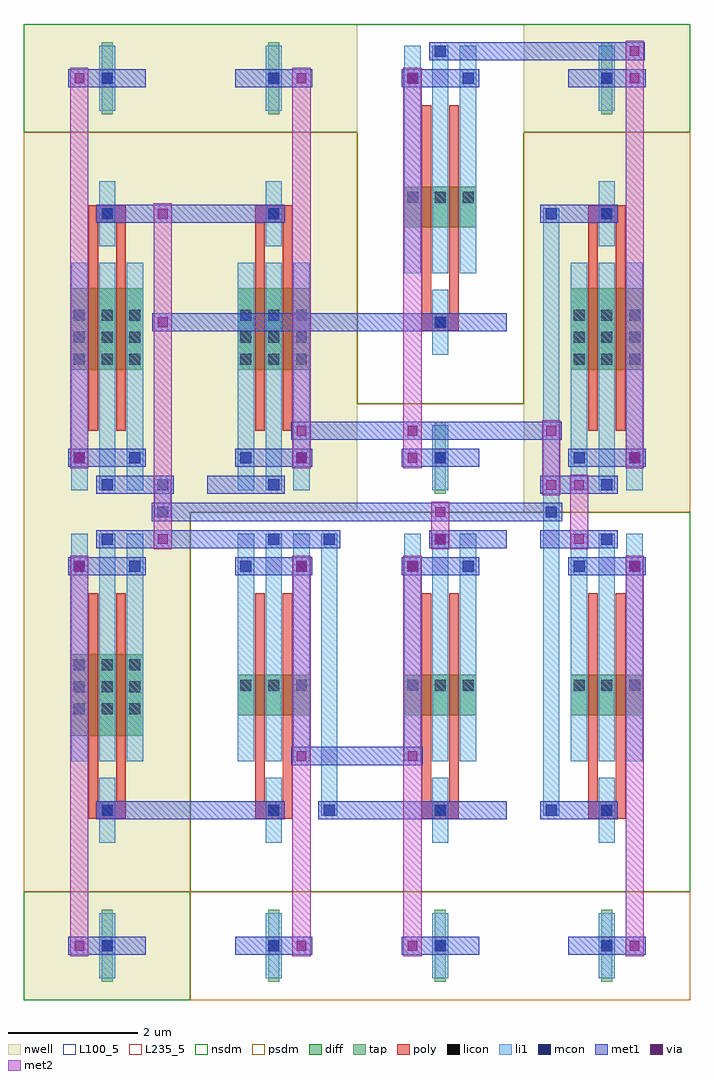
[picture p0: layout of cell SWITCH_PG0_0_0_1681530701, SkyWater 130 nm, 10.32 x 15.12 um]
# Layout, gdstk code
from math import pi, radians
import gdstk
lib = gdstk.Library(unit=1e-6, precision=1e-09)
def R(c, l, rs):  # rectangles x0, y0, x1, y1
    for r in rs: c.add(gdstk.rectangle(r[:2], r[2:], *l))
def A(c, l, x, y, w, h, nx, ny, dx, dy):  # array of equal rectangles
    R(c, l, [(x+i*dx, y+j*dy, x+i*dx+w, y+j*dy+h) for i in range(nx) for j in range(ny)])
def P(c, l, *ps):  # polygons
    for p in ps: c.add(gdstk.Polygon(p, *l))
nwell = (64, 20)
diff = (65, 20)
tap = (65, 44)
poly = (66, 20)
licon = (66, 44)
li1 = (67, 20)
mcon = (67, 44)
met1 = (68, 20)
via = (68, 44)
met2 = (69, 20)
nsdm = (93, 44)
psdm = (94, 20)
L100_5 = (100, 5)
L235_5 = (235, 5)

nmos_s_18927041_x1_y1_16 = lib.new_cell('NMOS_S_18927041_X1_Y1_1681530695_1681530696_1681530701')
R(nmos_s_18927041_x1_y1_16, diff, [(0.735,2.52,1.845,3.15)])
R(nmos_s_18927041_x1_y1_16, tap, [(1.205,6.16,1.375,7.28)])
R(nmos_s_18927041_x1_y1_16, poly, [(1,1.26,1.15,4.62), (1.43,1.26,1.58,4.62), (1,4.485,1.58,4.755)])
A(nmos_s_18927041_x1_y1_16, licon, 0.775, 2.6, 0.17, 0.17, 3, 1, 0.43, 0)
R(nmos_s_18927041_x1_y1_16, licon, [(1.205,4.535,1.375,4.705), (1.205,6.635,1.375,6.805)])
A(nmos_s_18927041_x1_y1_16, li1, 0.735, 0.335, 0.25, 3.53, 3, 1, 0.43, 0)
R(nmos_s_18927041_x1_y1_16, li1, [(1.165,4.115,1.415,5.125), (1.165,6.215,1.415,7.225)])
R(nmos_s_18927041_x1_y1_16, mcon, [(1.205,0.335,1.375,0.505), (0.775,0.755,0.945,0.925), (1.635,0.755,1.805,0.925), (1.205,4.535,1.375,4.705), (1.205,6.635,1.375,6.805)])
R(nmos_s_18927041_x1_y1_16, met1, [(0.26,0.28,1.46,0.56), (0.69,0.7,1.89,0.98), (0.26,4.48,1.46,4.76), (0.69,6.58,1.89,6.86)])
R(nmos_s_18927041_x1_y1_16, via, [(1.645,0.765,1.795,0.915), (1.645,6.645,1.795,6.795)])
R(nmos_s_18927041_x1_y1_16, met2, [(1.58,0.68,1.86,6.88)])
R(nmos_s_18927041_x1_y1_16, nsdm, [(0,0,2.58,5.88)])
R(nmos_s_18927041_x1_y1_16, psdm, [(0,5.88,2.58,7.56)])
R(nmos_s_18927041_x1_y1_16, L100_5, [(0,0,2.58,7.56)])

pmos_s_92403763_x1_y1_16 = lib.new_cell('PMOS_S_92403763_X1_Y1_1681530696_1681530696_1681530701')
R(pmos_s_92403763_x1_y1_16, nwell, [(0,0,2.58,7.56)])
R(pmos_s_92403763_x1_y1_16, diff, [(0.735,2.205,1.845,3.465)])
R(pmos_s_92403763_x1_y1_16, tap, [(1.205,6.16,1.375,7.28)])
R(pmos_s_92403763_x1_y1_16, poly, [(1,1.26,1.15,4.62), (1.43,1.26,1.58,4.62), (1,4.485,1.58,4.755)])
A(pmos_s_92403763_x1_y1_16, licon, 0.775, 2.285, 0.17, 0.17, 3, 3, 0.43, 0.34)
R(pmos_s_92403763_x1_y1_16, licon, [(1.205,4.535,1.375,4.705), (1.205,6.635,1.375,6.805)])
A(pmos_s_92403763_x1_y1_16, li1, 0.735, 0.335, 0.25, 3.53, 3, 1, 0.43, 0)
R(pmos_s_92403763_x1_y1_16, li1, [(1.165,4.115,1.415,5.125), (1.165,6.215,1.415,7.225)])
R(pmos_s_92403763_x1_y1_16, mcon, [(1.205,0.335,1.375,0.505), (0.775,0.755,0.945,0.925), (1.635,0.755,1.805,0.925), (1.205,4.535,1.375,4.705), (1.205,6.635,1.375,6.805)])
R(pmos_s_92403763_x1_y1_16, met1, [(0.26,0.28,1.46,0.56), (0.69,0.7,1.89,0.98), (0.26,4.48,1.46,4.76), (0.69,6.58,1.89,6.86)])
R(pmos_s_92403763_x1_y1_16, via, [(1.645,0.765,1.795,0.915), (1.645,6.645,1.795,6.795)])
R(pmos_s_92403763_x1_y1_16, met2, [(1.58,0.68,1.86,6.88)])
R(pmos_s_92403763_x1_y1_16, nsdm, [(0,5.88,2.58,7.56)])
R(pmos_s_92403763_x1_y1_16, psdm, [(0,0,2.58,5.88)])
R(pmos_s_92403763_x1_y1_16, L100_5, [(0,0,2.58,7.56)])

inv_26057185_pg0_0_0_168 = lib.new_cell('INV_26057185_PG0_0_0_1681530696_1681530701')
R(inv_26057185_pg0_0_0_168, li1, [(0.305,2.855,0.555,3.025), (0.305,2.855,0.555,3.025), (0.305,2.94,0.555,12.18), (0.305,12.095,0.555,12.265), (0.305,12.095,0.555,12.265)])
R(inv_26057185_pg0_0_0_168, mcon, [(0.345,2.855,0.515,3.025), (0.345,2.855,0.515,3.025), (0.345,12.095,0.515,12.265), (0.345,12.095,0.515,12.265)])
R(inv_26057185_pg0_0_0_168, met1, [(0.26,2.8,0.6,3.08), (0.26,2.8,0.6,3.08), (0.7,7,1.02,7.28), (0.7,7,1.02,7.28), (0.7,7.84,1.02,8.12), (0.7,7.84,1.02,8.12), (0.26,12.04,0.6,12.32), (0.26,12.04,0.6,12.32)])
P(inv_26057185_pg0_0_0_168, met1, [(0,0),(0,0),(0,0),(0,0)],
  [(0,0),(0,0),(0,0),(0,0)],
  [(0,0),(0,0),(0,0),(0,0)],
  [(0,0),(0,0),(0,0),(0,0)])
R(inv_26057185_pg0_0_0_168, via, [(0.785,7.065,0.935,7.215), (0.785,7.065,0.935,7.215), (0.785,7.905,0.935,8.055), (0.785,7.905,0.935,8.055)])
R(inv_26057185_pg0_0_0_168, met2, [(0.72,6.98,1,7.3), (0.72,6.98,1,7.3), (0.72,7.14,1,7.98), (0.72,7.82,1,8.14), (0.72,7.82,1,8.14)])
P(inv_26057185_pg0_0_0_168, met2, [(0,0),(0,0),(0,0),(0,0)],
  [(0,0),(0,0),(0,0),(0,0)])
R(inv_26057185_pg0_0_0_168, L235_5, [(0,0,2.58,15.12)])
inv_26057185_pg0_0_0_168.add(gdstk.Reference(nmos_s_18927041_x1_y1_16, (0,7.56), x_reflection=True))
inv_26057185_pg0_0_0_168.add(gdstk.Reference(pmos_s_92403763_x1_y1_16, (0,7.56)))

c_nmos_s_18927041_x1_y1_16 = lib.new_cell('NMOS_S_18927041_X1_Y1_1681530697_1681530701')
R(c_nmos_s_18927041_x1_y1_16, diff, [(0.735,2.52,1.845,3.15)])
R(c_nmos_s_18927041_x1_y1_16, tap, [(1.205,6.16,1.375,7.28)])
R(c_nmos_s_18927041_x1_y1_16, poly, [(1,1.26,1.15,4.62), (1.43,1.26,1.58,4.62), (1,4.485,1.58,4.755)])
A(c_nmos_s_18927041_x1_y1_16, licon, 0.775, 2.6, 0.17, 0.17, 3, 1, 0.43, 0)
R(c_nmos_s_18927041_x1_y1_16, licon, [(1.205,4.535,1.375,4.705), (1.205,6.635,1.375,6.805)])
A(c_nmos_s_18927041_x1_y1_16, li1, 0.735, 0.335, 0.25, 3.53, 3, 1, 0.43, 0)
R(c_nmos_s_18927041_x1_y1_16, li1, [(1.165,4.115,1.415,5.125), (1.165,6.215,1.415,7.225)])
R(c_nmos_s_18927041_x1_y1_16, mcon, [(1.205,0.335,1.375,0.505), (0.775,0.755,0.945,0.925), (1.635,0.755,1.805,0.925), (1.205,4.535,1.375,4.705), (1.205,6.635,1.375,6.805)])
R(c_nmos_s_18927041_x1_y1_16, met1, [(0.26,0.28,1.46,0.56), (0.69,0.7,1.89,0.98), (0.26,4.48,1.46,4.76), (0.69,6.58,1.89,6.86)])
R(c_nmos_s_18927041_x1_y1_16, via, [(1.645,0.765,1.795,0.915), (1.645,6.645,1.795,6.795)])
R(c_nmos_s_18927041_x1_y1_16, met2, [(1.58,0.68,1.86,6.88)])
R(c_nmos_s_18927041_x1_y1_16, nsdm, [(0,0,2.58,5.88)])
R(c_nmos_s_18927041_x1_y1_16, psdm, [(0,5.88,2.58,7.56)])
R(c_nmos_s_18927041_x1_y1_16, L100_5, [(0,0,2.58,7.56)])

c_pmos_s_92403763_x1_y1_16 = lib.new_cell('PMOS_S_92403763_X1_Y1_1681530698_1681530701')
R(c_pmos_s_92403763_x1_y1_16, nwell, [(0,0,2.58,7.56)])
R(c_pmos_s_92403763_x1_y1_16, diff, [(0.735,2.205,1.845,3.465)])
R(c_pmos_s_92403763_x1_y1_16, tap, [(1.205,6.16,1.375,7.28)])
R(c_pmos_s_92403763_x1_y1_16, poly, [(1,1.26,1.15,4.62), (1.43,1.26,1.58,4.62), (1,4.485,1.58,4.755)])
A(c_pmos_s_92403763_x1_y1_16, licon, 0.775, 2.285, 0.17, 0.17, 3, 3, 0.43, 0.34)
R(c_pmos_s_92403763_x1_y1_16, licon, [(1.205,4.535,1.375,4.705), (1.205,6.635,1.375,6.805)])
A(c_pmos_s_92403763_x1_y1_16, li1, 0.735, 0.335, 0.25, 3.53, 3, 1, 0.43, 0)
R(c_pmos_s_92403763_x1_y1_16, li1, [(1.165,4.115,1.415,5.125), (1.165,6.215,1.415,7.225)])
R(c_pmos_s_92403763_x1_y1_16, mcon, [(1.205,0.335,1.375,0.505), (0.775,0.755,0.945,0.925), (1.635,0.755,1.805,0.925), (1.205,4.535,1.375,4.705), (1.205,6.635,1.375,6.805)])
R(c_pmos_s_92403763_x1_y1_16, met1, [(0.26,0.28,1.46,0.56), (0.69,0.7,1.89,0.98), (0.26,4.48,1.46,4.76), (0.69,6.58,1.89,6.86)])
R(c_pmos_s_92403763_x1_y1_16, via, [(1.645,0.765,1.795,0.915), (1.645,6.645,1.795,6.795)])
R(c_pmos_s_92403763_x1_y1_16, met2, [(1.58,0.68,1.86,6.88)])
R(c_pmos_s_92403763_x1_y1_16, nsdm, [(0,5.88,2.58,7.56)])
R(c_pmos_s_92403763_x1_y1_16, psdm, [(0,0,2.58,5.88)])
R(c_pmos_s_92403763_x1_y1_16, L100_5, [(0,0,2.58,7.56)])

switch_pg0_0_0_168153070 = lib.new_cell('SWITCH_PG0_0_0_1681530701')
R(switch_pg0_0_0_168153070, li1, [(4.605,2.855,4.855,3.025), (4.605,2.855,4.855,3.025), (4.605,2.94,4.855,7.14), (4.605,7.055,4.855,7.225), (4.605,7.055,4.855,7.225), (2.025,7.475,2.275,7.645), (2.025,7.475,2.275,7.645), (2.025,7.475,2.275,7.645), (2.025,7.475,2.275,7.645), (8.045,7.475,8.295,7.645), (8.045,7.475,8.295,7.645), (2.025,7.56,2.275,7.98), (2.025,7.895,2.275,8.065), (2.025,7.895,2.275,8.065), (2.025,7.895,2.275,8.065), (2.025,7.895,2.275,8.065)])
P(switch_pg0_0_0_168153070, li1, [(0,0),(0,0),(0,0),(0,0)])
R(switch_pg0_0_0_168153070, mcon, [(4.645,2.855,4.815,3.025), (4.645,2.855,4.815,3.025), (4.645,7.055,4.815,7.225), (4.645,7.055,4.815,7.225), (2.065,7.475,2.235,7.645), (2.065,7.475,2.235,7.645), (2.065,7.475,2.235,7.645), (2.065,7.475,2.235,7.645), (8.085,7.475,8.255,7.645), (8.085,7.475,8.255,7.645), (2.065,7.895,2.235,8.065), (2.065,7.895,2.235,8.065), (2.065,7.895,2.235,8.065), (2.065,7.895,2.235,8.065)])
R(switch_pg0_0_0_168153070, met1, [(2.15,2.8,3.01,3.08), (4.56,2.8,4.9,3.08), (4.56,2.8,4.9,3.08), (4.73,2.8,6.45,3.08), (4.14,3.64,4.46,3.92), (4.14,3.64,4.46,3.92), (4.3,3.64,6.02,3.92), (5.86,3.64,6.18,3.92), (5.86,3.64,6.18,3.92), (1.99,7,2.31,7.28), (1.99,7,2.31,7.28), (1.99,7,2.31,7.28), (1.99,7,2.31,7.28), (1.99,7,2.31,7.28), (1.99,7,2.31,7.28), (1.99,7,2.31,7.28), (1.99,7,2.31,7.28), (2.15,7,3.01,7.28), (3.87,7,4.73,7.28), (4.56,7,4.9,7.28), (4.56,7,4.9,7.28), (6.29,7,6.61,7.28), (6.29,7,6.61,7.28), (6.29,7,6.61,7.28), (6.29,7,6.61,7.28), (1.98,7.42,2.32,7.7), (1.98,7.42,2.32,7.7), (1.98,7.42,2.32,7.7), (1.98,7.42,2.32,7.7), (2.15,7.42,6.45,7.7), (6.29,7.42,6.61,7.7), (6.29,7.42,6.61,7.7), (6.29,7.42,6.61,7.7), (6.29,7.42,6.61,7.7), (6.45,7.42,8.17,7.7), (8,7.42,8.34,7.7), (8,7.42,8.34,7.7), (1.98,7.84,2.32,8.12), (1.98,7.84,2.32,8.12), (1.98,7.84,2.32,8.12), (1.98,7.84,2.32,8.12), (8.01,7.84,8.33,8.12), (8.01,7.84,8.33,8.12), (4.14,8.68,4.46,8.96), (4.14,8.68,4.46,8.96), (4.14,8.68,4.46,8.96), (4.14,8.68,4.46,8.96), (4.3,8.68,6.02,8.96), (5.86,8.68,6.18,8.96), (5.86,8.68,6.18,8.96), (5.86,8.68,6.18,8.96), (5.86,8.68,6.18,8.96), (6.02,8.68,8.17,8.96), (8.01,8.68,8.33,8.96), (8.01,8.68,8.33,8.96), (1.99,10.36,2.31,10.64), (1.99,10.36,2.31,10.64), (1.99,10.36,2.31,10.64), (1.99,10.36,2.31,10.64), (2.15,10.36,6.45,10.64), (1.99,12.04,2.31,12.32), (1.99,12.04,2.31,12.32), (1.99,12.04,2.31,12.32), (1.99,12.04,2.31,12.32), (1.99,12.04,2.31,12.32), (1.99,12.04,2.31,12.32), (1.99,12.04,2.31,12.32), (1.99,12.04,2.31,12.32), (2.15,12.04,3.01,12.32), (7.31,14.56,9.46,14.84), (9.3,14.56,9.62,14.84), (9.3,14.56,9.62,14.84)])
P(switch_pg0_0_0_168153070, met1, [(0,0),(0,0),(0,0),(0,0)],
  [(0,0),(0,0),(0,0),(0,0)],
  [(0,0),(0,0),(0,0),(0,0)],
  [(0,0),(0,0),(0,0),(0,0)],
  [(0,0),(0,0),(0,0),(0,0)],
  [(0,0),(0,0),(0,0),(0,0)],
  [(0,0),(0,0),(0,0),(0,0)],
  [(0,0),(0,0),(0,0),(0,0)],
  [(0,0),(0,0),(0,0),(0,0)],
  [(0,0),(0,0),(0,0),(0,0)],
  [(0,0),(0,0),(0,0),(0,0)],
  [(0,0),(0,0),(0,0),(0,0)],
  [(0,0),(0,0),(0,0),(0,0)],
  [(0,0),(0,0),(0,0),(0,0)],
  [(0,0),(0,0),(0,0),(0,0)],
  [(0,0),(0,0),(0,0),(0,0)],
  [(0,0),(0,0),(0,0),(0,0)],
  [(0,0),(0,0),(0,0),(0,0)],
  [(0,0),(0,0),(0,0),(0,0)],
  [(0,0),(0,0),(0,0),(0,0)])
R(switch_pg0_0_0_168153070, via, [(4.225,3.705,4.375,3.855), (4.225,3.705,4.375,3.855), (5.945,3.705,6.095,3.855), (5.945,3.705,6.095,3.855), (2.075,7.065,2.225,7.215), (2.075,7.065,2.225,7.215), (2.075,7.065,2.225,7.215), (2.075,7.065,2.225,7.215), (2.075,7.065,2.225,7.215), (2.075,7.065,2.225,7.215), (2.075,7.065,2.225,7.215), (2.075,7.065,2.225,7.215), (6.375,7.065,6.525,7.215), (6.375,7.065,6.525,7.215), (6.375,7.065,6.525,7.215), (6.375,7.065,6.525,7.215), (6.375,7.485,6.525,7.635), (6.375,7.485,6.525,7.635), (6.375,7.485,6.525,7.635), (6.375,7.485,6.525,7.635), (8.095,7.905,8.245,8.055), (8.095,7.905,8.245,8.055), (4.225,8.745,4.375,8.895), (4.225,8.745,4.375,8.895), (4.225,8.745,4.375,8.895), (4.225,8.745,4.375,8.895), (5.945,8.745,6.095,8.895), (5.945,8.745,6.095,8.895), (5.945,8.745,6.095,8.895), (5.945,8.745,6.095,8.895), (8.095,8.745,8.245,8.895), (8.095,8.745,8.245,8.895), (2.075,10.425,2.225,10.575), (2.075,10.425,2.225,10.575), (2.075,10.425,2.225,10.575), (2.075,10.425,2.225,10.575), (2.075,12.105,2.225,12.255), (2.075,12.105,2.225,12.255), (2.075,12.105,2.225,12.255), (2.075,12.105,2.225,12.255), (2.075,12.105,2.225,12.255), (2.075,12.105,2.225,12.255), (2.075,12.105,2.225,12.255), (2.075,12.105,2.225,12.255), (9.385,14.625,9.535,14.775), (9.385,14.625,9.535,14.775)])
R(switch_pg0_0_0_168153070, met2, [(4.16,3.62,4.44,3.94), (4.16,3.62,4.44,3.94), (5.88,3.62,6.16,3.94), (5.88,3.62,6.16,3.94), (2.01,6.98,2.29,7.3), (2.01,6.98,2.29,7.3), (2.01,6.98,2.29,7.3), (2.01,6.98,2.29,7.3), (2.01,6.98,2.29,7.3), (2.01,6.98,2.29,7.3), (2.01,6.98,2.29,7.3), (2.01,6.98,2.29,7.3), (6.31,6.98,6.59,7.3), (6.31,6.98,6.59,7.3), (6.31,6.98,6.59,7.3), (6.31,6.98,6.59,7.3), (2.01,7.14,2.29,12.18), (6.31,7.14,6.59,7.56), (6.31,7.4,6.59,7.72), (6.31,7.4,6.59,7.72), (6.31,7.4,6.59,7.72), (6.31,7.4,6.59,7.72), (8.03,7.82,8.31,8.14), (8.03,7.82,8.31,8.14), (8.03,7.98,8.31,8.82), (4.16,8.66,4.44,8.98), (4.16,8.66,4.44,8.98), (4.16,8.66,4.44,8.98), (4.16,8.66,4.44,8.98), (5.88,8.66,6.16,8.98), (5.88,8.66,6.16,8.98), (5.88,8.66,6.16,8.98), (5.88,8.66,6.16,8.98), (8.03,8.66,8.31,8.98), (8.03,8.66,8.31,8.98), (2.01,10.34,2.29,10.66), (2.01,10.34,2.29,10.66), (2.01,10.34,2.29,10.66), (2.01,10.34,2.29,10.66), (2.01,12.02,2.29,12.34), (2.01,12.02,2.29,12.34), (2.01,12.02,2.29,12.34), (2.01,12.02,2.29,12.34), (2.01,12.02,2.29,12.34), (2.01,12.02,2.29,12.34), (2.01,12.02,2.29,12.34), (2.01,12.02,2.29,12.34), (9.32,14.28,9.6,14.7), (9.32,14.54,9.6,14.86), (9.32,14.54,9.6,14.86)])
P(switch_pg0_0_0_168153070, met2, [(0,0),(0,0),(0,0),(0,0)],
  [(0,0),(0,0),(0,0),(0,0)],
  [(0,0),(0,0),(0,0),(0,0)],
  [(0,0),(0,0),(0,0),(0,0)],
  [(0,0),(0,0),(0,0),(0,0)],
  [(0,0),(0,0),(0,0),(0,0)],
  [(0,0),(0,0),(0,0),(0,0)],
  [(0,0),(0,0),(0,0),(0,0)])
R(switch_pg0_0_0_168153070, L235_5, [(0,0,10.32,15.12)])
switch_pg0_0_0_168153070.add(gdstk.Reference(inv_26057185_pg0_0_0_168, (7.74,0)))
switch_pg0_0_0_168153070.add(gdstk.Reference(c_nmos_s_18927041_x1_y1_16, (2.58,7.56), x_reflection=True))
switch_pg0_0_0_168153070.add(gdstk.Reference(c_nmos_s_18927041_x1_y1_16, (7.74,7.56), rotation=pi))
switch_pg0_0_0_168153070.add(gdstk.Reference(c_nmos_s_18927041_x1_y1_16, (7.74,15.12), rotation=pi))
switch_pg0_0_0_168153070.add(gdstk.Reference(c_pmos_s_92403763_x1_y1_16, (2.58,7.56), rotation=pi))
switch_pg0_0_0_168153070.add(gdstk.Reference(c_pmos_s_92403763_x1_y1_16, (2.58,7.56), rotation=pi, x_reflection=True))
switch_pg0_0_0_168153070.add(gdstk.Reference(c_pmos_s_92403763_x1_y1_16, (2.58,7.56)))

lib.write_gds('SWITCH_PG0_0_0_1681530701.gds')
